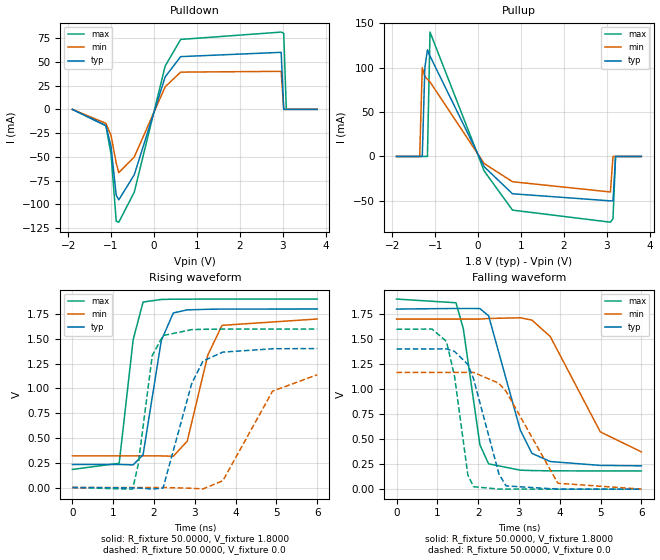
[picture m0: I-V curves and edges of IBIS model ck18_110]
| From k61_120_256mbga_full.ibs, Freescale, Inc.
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|   Model ck18_110
[Model]  ck18_110
Model_type Output
Polarity   Non-Inverting
Enable   Active-High
Vmeas =  0.9000V
Cref =   5.0000pF
Rref =   50.0000
C_comp   2.8000pF   2.5000pF   3.3000pF
[Temperature Range]   25.0000   0.1250k   -40.0000
[Voltage Range]   1.8000V   1.7000V   1.9000V
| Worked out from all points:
|   slope of the pulldown table from 0 to 0.27 V, typ, clamps not added: 7.69 ohm
|   slope of the pullup table from 0 to 0.27 V, typ, clamps not added: 13.1 ohm
|   rising waveform, R_fixture 50.0000, V_fixture 1.8000: 20-80 % time 333ps typ, 477ps min, 251ps max; typ from 0.232 V to 1.8 V
|   rising waveform, R_fixture 50.0000, V_fixture 0.0: 20-80 % time 510ps typ, 870ps min, 292ps max; typ from 0 V to 1.4 V
|   falling waveform, R_fixture 50.0000, V_fixture 1.8000: 20-80 % time 585ps typ, 981ps min, 351ps max; typ from 1.8 V to 0.233 V
|   falling waveform, R_fixture 50.0000, V_fixture 0.0: 20-80 % time 552ps typ, 879ps min, 328ps max; typ from 1.4 V to 0 V
[Pulldown]
|Voltage   I(typ)   I(min)   I(max)
-1.9V     0A         0A         0A
-1.12V    -17mA      -14.72mA   -17.3mA
-1V       -39.37mA   -27.47mA   -47.2mA
-880mV    -90.32mA   -56.59mA   -117.6mA
-820mV    -95.2mA    -66.52mA   -118.7mA
-460mV    -68.85mA   -50.15mA   -87.16mA
260mV     34.19mA    23.75mA    45.61mA
620mV     55.49mA    39.18mA    73.57mA
2.96V     60mA       40mA       81.3mA
3.02V     0A         0A         80mA
3.08V     0A         0A         0A
3.8V      0A         0A         0A
[Pullup]
|Voltage   I(typ)   I(min)   I(max)
-1.9V     0A         0A         0A
-1.36V    0A         0A         0A
-1.3V     0A         100mA      0A
-1.24V    100mA      90mA       0A
-1.18V    120mA      87mA       0A
-1.12V    113mA      84mA       140mA
140mV     -11.55mA   -7.926mA   -16.27mA
800mV     -42mA      -28.43mA   -60.4mA
3.08V     -50mA      -40mA      -74mA
3.14V     -50mA      0A         -70mA
3.2V      0A         0A         0A
3.8V      0A         0A         0A
[Ramp]
| variable   typ   min   max
dV/dt_r  0.8407/0.5097n   0.6824/0.8691n   0.9585/0.2923n
dV/dt_f  0.9400/0.5851n   0.7962/0.9791n   1.0307/0.3509n
R_load = 50.0000
[Rising Waveform]
R_fixture= 50.0000
V_fixture= 1.8000
V_fixture_min= 1.7000
V_fixture_max= 1.9000
|time   V(typ)   V(min)   V(max)
0s        232.4mV    319.4mV    182.2mV
1.147ns   232.5mV    319.4mV    244.5mV
1.49ns    228.2mV    319.4mV    1.492V
1.732ns   330.7mV    319.4mV    1.87V
2.178ns   1.481V     318.6mV    1.896V
2.473ns   1.76V      315.5mV    1.899V
2.814ns   1.791V     466.6mV    1.899V
3.32ns    1.797V     1.337V     1.9V
3.667ns   1.799V     1.635V     1.9V
6ns       1.8V       1.699V     1.9V
[Rising Waveform]
R_fixture= 50.0000
V_fixture= 0.0
|time   V(typ)   V(min)   V(max)
0s        2.762nV    224.6nV    1.138nV
1.476ns   -3.255mV   179.4nV    -16.57mV
1.612ns   -4.754mV   -3.256uV   232.1mV
1.957ns   -15.51mV   157.8uV    1.33V
2.221ns   -6.339mV   151.7uV    1.532V
2.924ns   1.049V     -7.359mV   1.592V
3.199ns   1.275V     -14.74mV   1.595V
3.687ns   1.365V     68.22mV    1.597V
4.905ns   1.399V     971.6mV    1.597V
6ns       1.401V     1.137V     1.598V
[Falling Waveform]
R_fixture= 50.0000
V_fixture= 1.8000
V_fixture_min= 1.7000
V_fixture_max= 1.9000
|time   V(typ)   V(min)   V(max)
0s        1.8V       1.7V       1.9V
1.458ns   1.806V     1.7V       1.863V
1.637ns   1.806V     1.7V       1.604V
2.044ns   1.805V     1.7V       443.4mV
2.257ns   1.733V     1.706V     253mV
3.034ns   589.9mV    1.713V     189.7mV
3.318ns   358.2mV    1.69V      185.9mV
3.767ns   276.2mV    1.526V     183.4mV
4.994ns   237.4mV    572.6mV    182.2mV
6ns       233.3mV    373mV      182.2mV
[Falling Waveform]
R_fixture= 50.0000
V_fixture= 0.0
|time   V(typ)   V(min)   V(max)
0s        1.401V     1.167V     1.598V
871.5ps   1.401V     1.167V     1.6V
1.224ns   1.402V     1.167V     1.477V
1.422ns   1.377V     1.167V     1.129V
1.749ns   1.246V     1.167V     141.1mV
1.888ns   1.103V     1.167V     24.45mV
2.509ns   153.1mV    1.058V     988.2uV
2.684ns   32.57mV    978.3mV    635.6uV
3.954ns   502.3uV    59.26mV    24.4uV
6ns       13.19uV    437.2uV    127.6nV
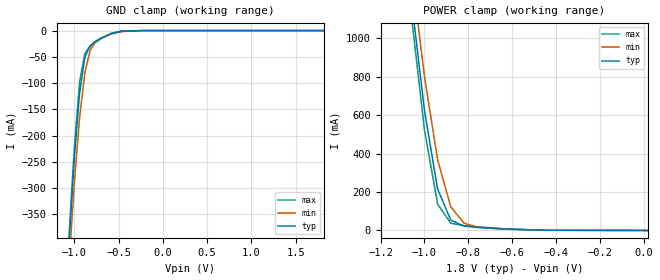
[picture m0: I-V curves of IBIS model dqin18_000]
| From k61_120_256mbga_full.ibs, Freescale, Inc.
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|   Model dqin18_000
[Model]  dqin18_000
Model_type Input
Polarity   Non-Inverting
Enable   Active-High
Vinl =   0.6500V
Vinh =   1.1500V
C_comp   2.8000pF   2.5000pF   3.3000pF
[Temperature Range]   25.0000   0.1250k   -40.0000
[Voltage Range]   1.8000V   1.7000V   1.9000V
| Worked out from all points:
|   GND clamp passes 1 mA (typ) near -0.46 V on its own axis
|   POWER clamp passes 1 mA (typ) near -0.45 V on its own axis
[GND_clamp]
|Voltage   I(typ)   I(min)   I(max)
-1.9V     -3.326A    -3.292A    -3.364A
-1.06V    -406.5mA   -447.4mA   -394.6mA
-1V       -245.1mA   -292.9mA   -225.5mA
-940mV    -119.4mA   -166.1mA   -98.22mA
-880mV    -50.5mA    -79.89mA   -43.13mA
-820mV    -28.4mA    -37.26mA   -29.9mA
-760mV    -20.29mA   -21.31mA   -22.38mA
-700mV    -14.5mA    -14.44mA   -15.67mA
-580mV    -5.551mA   -6.474mA   -5.066mA
-460mV    -1.018mA   -1.866mA   -602.3uA
-220mV    -979.5nA   -15.35uA   -59.46nA
1.82V     915.2pA    951.9nA    210.6pA
[POWER_clamp]
|Voltage   I(typ)   I(min)   I(max)
-1.9V     11.94A     11.89A     12.02A
-1.06V    1.204A     1.363A     1.122A
-1V       623.7mA    800mA      522.5mA
-940mV    215.1mA    367.1mA    136.6mA
-880mV    53.67mA    122.9mA    37.6mA
-820mV    23.13mA    38.48mA    24.96mA
-760mV    15.75mA    17.21mA    18.82mA
-640mV    7.758mA    7.284mA    9.105mA
-460mV    1.139mA    1.585mA    966.7uA
20mV      398.7pA    26.73nA    225pA
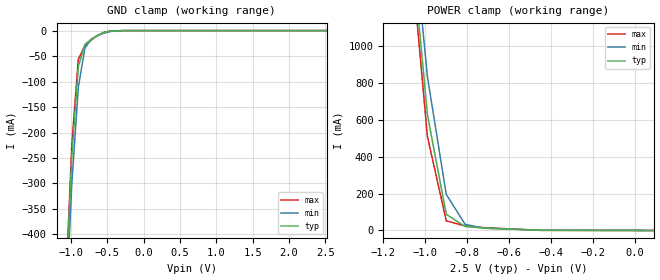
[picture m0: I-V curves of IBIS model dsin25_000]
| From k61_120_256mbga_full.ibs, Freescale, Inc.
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|   Model dsin25_000
[Model]  dsin25_000
Model_type Input
Polarity   Non-Inverting
Enable   Active-High
Vinl =   0.9400V
Vinh =   1.5600V
C_comp   2.8000pF   2.5000pF   3.3000pF
[Temperature Range]   25.0000   0.1250k   -40.0000
[Voltage Range]   2.5000V   2.3000V   2.7000V
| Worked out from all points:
|   GND clamp passes 1 mA (typ) near -0.45 V on its own axis
|   POWER clamp passes 1 mA (typ) near -0.45 V on its own axis
[GND_clamp]
|Voltage   I(typ)   I(min)   I(max)
-2.7V     -7.356A    -7.293A    -7.42A
-1.08V    -532.8mA   -574.3mA   -523.6mA
-990mV    -247.4mA   -301.7mA   -224.7mA
-900mV    -70.56mA   -111.2mA   -56.24mA
-810mV    -27.41mA   -34.5mA    -29.36mA
-720mV    -16.75mA   -16.71mA   -18.34mA
-630mV    -9.057mA   -9.559mA   -9.134mA
-540mV    -3.599mA   -4.686mA   -2.944mA
-450mV    -871.2uA   -1.673mA   -498uA
-270mV    -6.1uA     -54.75uA   -659.2nA
2.52V     1.073nA    13.44uA    292.2pA
[POWER_clamp]
|Voltage   I(typ)   I(min)   I(max)
-2.7V     28.59A     28.4A      28.77A
-1.08V    1.721A     1.892A     1.641A
-990mV    627.2mA    833mA      508.6mA
-900mV    87.49mA    195.4mA    52.32mA
-810mV    21.66mA    33.19mA    24.16mA
-720mV    12.85mA    12.43mA    15.46mA
-450mV    973.3uA    1.424mA    784.9uA
90mV      411.9pA    14.45nA    314.3pA
